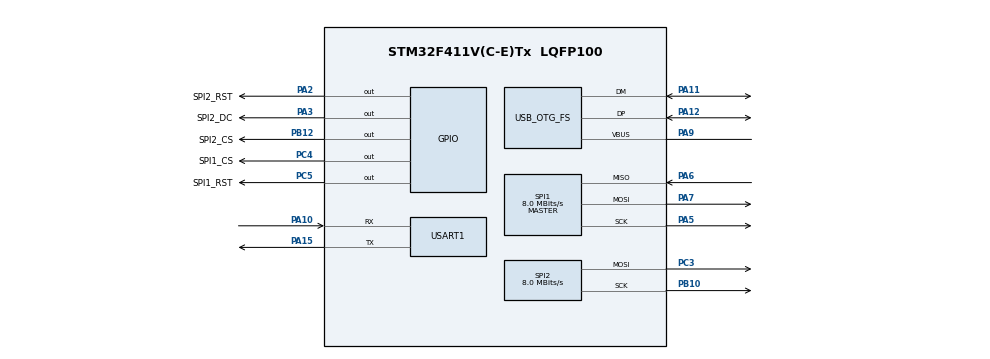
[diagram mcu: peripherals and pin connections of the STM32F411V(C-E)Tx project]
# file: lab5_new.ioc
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Mcu.Family=STM32F4
Mcu.Name=STM32F411V(C-E)Tx
Mcu.Package=LQFP100
NVIC.OTG_FS_IRQn=true\:0\:0\:false\:false\:true\:false\:true\:true
NVIC.PriorityGroup=NVIC_PRIORITYGROUP_4
NVIC.SPI2_IRQn=true\:0\:0\:false\:false\:true\:true\:true\:true
PA10.Mode=Asynchronous
PA10.Signal=USART1_RX
PA11.Mode=Device_Only
PA11.Signal=USB_OTG_FS_DM
PA12.Mode=Device_Only
PA12.Signal=USB_OTG_FS_DP
PA13.Mode=Serial_Wire
PA13.Signal=SYS_JTMS-SWDIO
PA14.Mode=Serial_Wire
PA14.Signal=SYS_JTCK-SWCLK
PA15.Mode=Asynchronous
PA15.Signal=USART1_TX
PA2.GPIO_Label=SPI2_RST
PA2.Signal=GPIO_Output
PA3.GPIO_Label=SPI2_DC
PA3.Signal=GPIO_Output
PA5.Mode=Full_Duplex_Master
PA5.Signal=SPI1_SCK
PA6.Mode=Full_Duplex_Master
PA6.Signal=SPI1_MISO
PA7.Mode=Full_Duplex_Master
PA7.Signal=SPI1_MOSI
PA9.Mode=Activate_VBUS
PA9.Signal=USB_OTG_FS_VBUS
PB10.Mode=TX_Only_Simplex_Unidirect_Master
PB10.Signal=SPI2_SCK
PB12.GPIO_Label=SPI2_CS
PB12.Signal=GPIO_Output
PC3.Mode=TX_Only_Simplex_Unidirect_Master
PC3.Signal=SPI2_MOSI
PC4.GPIO_Label=SPI1_CS
PC4.PinState=GPIO_PIN_SET
PC4.Signal=GPIO_Output
PC5.GPIO_Label=SPI1_RST
PC5.PinState=GPIO_PIN_SET
PC5.Signal=GPIO_Output
PH0\ -\ OSC_IN.Mode=HSE-External-Oscillator
PH0\ -\ OSC_IN.Signal=RCC_OSC_IN
PH1\ -\ OSC_OUT.Mode=HSE-External-Oscillator
PH1\ -\ OSC_OUT.Signal=RCC_OSC_OUT
ProjectManager.HeapSize=0x200
ProjectManager.StackSize=0x400
ProjectManager.TargetToolchain=STM32CubeIDE
RCC.48MHZClocksFreq_Value=48000000
RCC.AHBCLKDivider=RCC_SYSCLK_DIV2
RCC.AHBFreq_Value=16000000
RCC.APB1Freq_Value=16000000
RCC.APB1TimFreq_Value=16000000
RCC.APB2Freq_Value=16000000
RCC.APB2TimFreq_Value=16000000
RCC.CortexFreq_Value=16000000
RCC.HCLKFreq_Value=16000000
RCC.HSE_VALUE=25000000
RCC.HSI_VALUE=16000000
RCC.LSE_VALUE=32768
RCC.PLLM=25
RCC.PLLP=RCC_PLLP_DIV6
RCC.SYSCLKFreq_VALUE=32000000
RCC.SYSCLKSource=RCC_SYSCLKSOURCE_PLLCLK
RCC.VCOOutputFreq_Value=192000000
SPI1.CalculateBaudRate=8.0 MBits/s
SPI1.Direction=SPI_DIRECTION_2LINES
SPI1.Mode=SPI_MODE_MASTER
SPI1.VirtualType=VM_MASTER
SPI2.CalculateBaudRate=8.0 MBits/s
SPI2.Direction=SPI_DIRECTION_2LINES
SPI2.Mode=SPI_MODE_MASTER
SPI2.VirtualType=VM_MASTER
USART1.VirtualMode=VM_ASYNC
USB_DEVICE.CLASS_NAME_FS=CDC
USB_DEVICE.VirtualMode=Cdc
USB_DEVICE.VirtualModeFS=Cdc_FS
USB_OTG_FS.VirtualMode=Device_Only
VP_USB_DEVICE_VS_USB_DEVICE_CDC_FS.Mode=CDC_FS
board=custom

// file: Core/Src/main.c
/* USER CODE BEGIN Header */
/**
  ******************************************************************************
  * @file           : main.c
  * @brief          : Main program body
  ******************************************************************************
  * @attention
  *
  * Copyright (c) 2025 STMicroelectronics.
  * All rights reserved.
  *
  * This software is licensed under terms that can be found in the LICENSE file
  * in the root directory of this software component.
  * If no LICENSE file comes with this software, it is provided AS-IS.
  *
  ******************************************************************************
  */
/* USER CODE END Header */
#include "main.h"
#include "usb_device.h"

/* USER CODE BEGIN Includes */
#include <stdio.h>
#include <string.h>
#include <w5500_custom.h>
#include "dhcp.h"
#include "net.h"
#include "socket.h"
#include "ILI9341.h"
#include "llmnr.h"
/* USER CODE END Includes */

SPI_HandleTypeDef hspi1;
SPI_HandleTypeDef hspi2;

UART_HandleTypeDef huart1;

/* USER CODE BEGIN PV */
volatile uint32_t dhcp_tick_cnt = 0;
uint8_t chip_ver_g;
Screen ILI9341_Screen;

uint8_t is_websocket_active = 0;
/* USER CODE END PV */

void SystemClock_Config(void);
static void MX_GPIO_Init(void);
static void MX_SPI1_Init(void);
static void MX_USART1_UART_Init(void);
static void MX_SPI2_Init(void);

/* USER CODE BEGIN 0 */

void Timer_Callback_1s(void) {
    DHCP_time_handler();
}

/* USER CODE END 0 */

int main(void)
{

  /* MCU Configuration--------------------------------------------------------*/

  /* Reset of all peripherals, Initializes the Flash interface and the Systick. */
  HAL_Init();

  /* Configure the system clock */
  SystemClock_Config();

  /* Initialize all configured peripherals */
  MX_GPIO_Init();
  MX_SPI1_Init();
  MX_USART1_UART_Init();
  MX_SPI2_Init();
  /* USER CODE BEGIN 2 */

  ILI9341_init(&hspi2);

  Screen_Tiles_init(&ILI9341_Screen);

  ILI9341_fill_screen(&hspi2, &ILI9341_Screen, 0x0000); // 0x0000
  HAL_Delay(3000);

  printf("Resetting W5500...\r\n");

  HAL_GPIO_WritePin(GPIOC, GPIO_PIN_5, GPIO_PIN_RESET);
  HAL_Delay(10);
  HAL_GPIO_WritePin(GPIOC, GPIO_PIN_5, GPIO_PIN_SET);
  HAL_Delay(100);

  W5500_Init();
  Net_Init();

  status_init();

    // Initialize USB CDC device
  MX_USB_DEVICE_Init();

  // --- Start HTTP Server on Socket 1 ---
  uint8_t sock = 1;

    if(socket(sock, Sn_MR_TCP, 80, 0) == sock) {
        listen(sock);
        printf("Server started on port 80\r\n");
    } else {
        printf("Failed to open socket\r\n");
    }

    // --- Start LLMNR on Socket 2 ---
      uint8_t sock_llmnr = 2; // <--- 2. Виділяємо окремий сокет для LLMNR (UDP)
      LLMNR_Init(sock_llmnr); // <--- 3. Ініціалізуємо LLMNR
  /* USER CODE END 2 */
      uint32_t last_status_ms = HAL_GetTick();
  /* Infinite loop */
  while (1)
  {

    /* USER CODE BEGIN 3 */
	  uint32_t now = HAL_GetTick();

	  if ((now - last_status_ms) >= 1000)
		{
			last_status_ms = now;
			status_update();
		}

	  wiz_NetInfo cur_net_info;

	  wizchip_getnetinfo(&cur_net_info);

	  if (cur_net_info.dhcp == NETINFO_DHCP) {
	       static uint32_t sec_timer = 0;
	       if (HAL_GetTick() - sec_timer >= 1000) {
	          sec_timer = HAL_GetTick();
	          DHCP_time_handler();
	       }
	       DHCP_run();
	  }

	  // ========== HTTP SERVER LOOP ==========
	  uint8_t status = getSn_SR(sock);

	  static uint8_t buffer[1024];

	  if (status == SOCK_CLOSED) {
		  if(socket(sock, Sn_MR_TCP, 80, 0) == sock) {
			  listen(sock);
			  is_websocket_active = 0; // Reset flag
			  printf("Socket Re-opened\r\n");
		  }
	  }

	  if (status == SOCK_ESTABLISHED) {
		if (getSn_RX_RSR(sock) > 0) {
		  int32_t recv_len = recv(sock, buffer, sizeof(buffer));

		  if (recv_len > 0) {
			  if (!is_websocket_active && strstr((char*)buffer, "Upgrade: websocket")) {
					  printf("WebSocket Upgrade Request Received\r\n");
					  if (WS_PerformHandshake(sock, (char*)buffer)) { //
						  is_websocket_active = 1;
						  printf("WebSocket Handshake Success!\r\n");
						  // IMPORTANT: DO NOT DISCONNECT HERE
				  }
			  }

			  // --- GET /status ---
			  else if (strstr((char*)buffer, "GET /status") != NULL) {

				  char json[256];
				  build_status_json(json, sizeof(json));

				  char header[128];
				  sprintf(header,
					  "HTTP/1.1 200 OK\r\n"
					  "Content-Type: application/json\r\n"
					  "Content-Length: %d\r\n\r\n",
					  (int)strlen(json)
				  );

				  send(sock, (uint8_t *)header, strlen(header));
				  send(sock, (uint8_t *)json, strlen(json));
			  }

			  // --- GET / ---
			  else if (!is_websocket_active && strstr((char*)buffer, "GET / ")) {
			                  // Updated HTML to use WebSocket Client (ws://)
			                  const char *html =
			                      "<html><head><title>STM32 WS</title></head><body>"
			                      "<h1>STM32 Monitor</h1>"
			                      "<div id='d' style='font-size:20px;font-family:monospace;'>Waiting...</div>"
			                      "<script>"
			                      "var ws = new WebSocket('ws://' + location.host);"
			                      "ws.onmessage = function(e){ document.getElementById('d').innerText = e.data; };"
			                      "ws.onclose = function(){ document.getElementById('d').innerText += ' (Closed)'; };"
			                      "</script>"
			                      "</body></html>";

			                  char header[128];
			                  sprintf(header,
			                      "HTTP/1.1 200 OK\r\n"
			                      "Content-Type: text/html\r\n"
			                      "Content-Length: %d\r\n\r\n",
			                      strlen(html)
			                  );
			                  send(sock, (uint8_t *)header, strlen(header));
			                  send(sock, (uint8_t *)html, strlen(html));

			                  // For standard HTTP, we MUST disconnect to finish the load
			                  disconnect(sock);
			  }

		  }

		}
	  }

	  if (status == SOCK_CLOSE_WAIT) {
	          disconnect(sock);
	          is_websocket_active = 0;
	          printf("Client Disconnected\r\n");
	  }
	  if (is_websocket_active) {
	              static uint32_t ws_timer = 0;
	              if (HAL_GetTick() - ws_timer >= 500) { // Send every 500ms
	                  ws_timer += 500;

	                  char json[128];
	                  // Simulate changing data
	                  sprintf(json, "{\"tick\":%lu, \"adc\":%d}", HAL_GetTick(), rand()%4096);

	                  WS_SendText(sock, json); //
	              }
	  }
	  // --- LLMNR Process ---
	  LLMNR_Process(sock_llmnr);
  }

  /* USER CODE END 3 */
}

void SystemClock_Config(void)
{
  RCC_OscInitTypeDef RCC_OscInitStruct = {0};
  RCC_ClkInitTypeDef RCC_ClkInitStruct = {0};

  /* Увімкнути живлення і виставити шкалу напруги */
  __HAL_RCC_PWR_CLK_ENABLE();
  __HAL_PWR_VOLTAGESCALING_CONFIG(PWR_REGULATOR_VOLTAGE_SCALE2);

  /* Налаштовуємо осцилятори: HSE + PLL */
  RCC_OscInitStruct.OscillatorType = RCC_OSCILLATORTYPE_HSE;
  RCC_OscInitStruct.HSEState = RCC_HSE_ON;
  RCC_OscInitStruct.PLL.PLLState = RCC_PLL_ON;
  RCC_OscInitStruct.PLL.PLLSource = RCC_PLLSOURCE_HSE;

  /* HSE=8MHz:
   * PLLM = 8   → VCO_IN = 1 MHz
   * PLLN = 336 → VCO_OUT = 336 MHz
   * PLLP = 4   → SYSCLK = 84 MHz
   * PLLQ = 7   → 336/7 = 48 MHz для USB
   */
  RCC_OscInitStruct.PLL.PLLM = 8;
  RCC_OscInitStruct.PLL.PLLN = 336;
  RCC_OscInitStruct.PLL.PLLP = RCC_PLLP_DIV4;
  RCC_OscInitStruct.PLL.PLLQ = 7;

  if (HAL_RCC_OscConfig(&RCC_OscInitStruct) != HAL_OK)
  {
    Error_Handler();
  }

  /* Шини */
  RCC_ClkInitStruct.ClockType = RCC_CLOCKTYPE_HCLK |
                                RCC_CLOCKTYPE_SYSCLK |
                                RCC_CLOCKTYPE_PCLK1 |
                                RCC_CLOCKTYPE_PCLK2;

  RCC_ClkInitStruct.SYSCLKSource = RCC_SYSCLKSOURCE_PLLCLK;  // 84 MHz
  RCC_ClkInitStruct.AHBCLKDivider = RCC_SYSCLK_DIV1;         // HCLK = 84 MHz
  RCC_ClkInitStruct.APB1CLKDivider = RCC_HCLK_DIV2;          // PCLK1 = 42 MHz
  RCC_ClkInitStruct.APB2CLKDivider = RCC_HCLK_DIV1;          // PCLK2 = 84 MHz

  if (HAL_RCC_ClockConfig(&RCC_ClkInitStruct, FLASH_LATENCY_2) != HAL_OK)
  {
    Error_Handler();
  }
}

static void MX_SPI1_Init(void)
{

  /* SPI1 parameter configuration*/
  hspi1.Instance = SPI1;
  hspi1.Init.Mode = SPI_MODE_MASTER;
  hspi1.Init.Direction = SPI_DIRECTION_2LINES;
  hspi1.Init.DataSize = SPI_DATASIZE_8BIT;
  hspi1.Init.CLKPolarity = SPI_POLARITY_LOW;
  hspi1.Init.CLKPhase = SPI_PHASE_1EDGE;
  hspi1.Init.NSS = SPI_NSS_SOFT;
  hspi1.Init.BaudRatePrescaler = SPI_BAUDRATEPRESCALER_2;
  hspi1.Init.FirstBit = SPI_FIRSTBIT_MSB;
  hspi1.Init.TIMode = SPI_TIMODE_DISABLE;
  hspi1.Init.CRCCalculation = SPI_CRCCALCULATION_DISABLE;
  hspi1.Init.CRCPolynomial = 10;
  if (HAL_SPI_Init(&hspi1) != HAL_OK)
  {
    Error_Handler();
  }

}

static void MX_SPI2_Init(void)
{

  /* SPI2 parameter configuration*/
  hspi2.Instance = SPI2;
  hspi2.Init.Mode = SPI_MODE_MASTER;
  hspi2.Init.Direction = SPI_DIRECTION_2LINES;
  hspi2.Init.DataSize = SPI_DATASIZE_8BIT;
  hspi2.Init.CLKPolarity = SPI_POLARITY_LOW;
  hspi2.Init.CLKPhase = SPI_PHASE_1EDGE;
  hspi2.Init.NSS = SPI_NSS_SOFT;
  hspi2.Init.BaudRatePrescaler = SPI_BAUDRATEPRESCALER_2;
  hspi2.Init.FirstBit = SPI_FIRSTBIT_MSB;
  hspi2.Init.TIMode = SPI_TIMODE_DISABLE;
  hspi2.Init.CRCCalculation = SPI_CRCCALCULATION_DISABLE;
  hspi2.Init.CRCPolynomial = 10;
  if (HAL_SPI_Init(&hspi2) != HAL_OK)
  {
    Error_Handler();
  }

}

static void MX_USART1_UART_Init(void)
{

  huart1.Instance = USART1;
  huart1.Init.BaudRate = 115200;
  huart1.Init.WordLength = UART_WORDLENGTH_8B;
  huart1.Init.StopBits = UART_STOPBITS_1;
  huart1.Init.Parity = UART_PARITY_NONE;
  huart1.Init.Mode = UART_MODE_TX_RX;
  huart1.Init.HwFlowCtl = UART_HWCONTROL_NONE;
  huart1.Init.OverSampling = UART_OVERSAMPLING_16;
  if (HAL_UART_Init(&huart1) != HAL_OK)
  {
    Error_Handler();
  }

}

static void MX_GPIO_Init(void)
{
  GPIO_InitTypeDef GPIO_InitStruct = {0};

  /* GPIO Ports Clock Enable */
  __HAL_RCC_GPIOH_CLK_ENABLE();
  __HAL_RCC_GPIOC_CLK_ENABLE();
  __HAL_RCC_GPIOA_CLK_ENABLE();
  __HAL_RCC_GPIOB_CLK_ENABLE();

  /*Configure GPIO pin Output Level */
  HAL_GPIO_WritePin(GPIOA, SPI2_RST_Pin|SPI2_DC_Pin, GPIO_PIN_RESET);

  /*Configure GPIO pin Output Level */
  HAL_GPIO_WritePin(GPIOC, SPI1_CS_Pin|SPI1_RST_Pin, GPIO_PIN_SET);

  /*Configure GPIO pin Output Level */
  HAL_GPIO_WritePin(SPI2_CS_GPIO_Port, SPI2_CS_Pin, GPIO_PIN_RESET);

  /*Configure GPIO pins : SPI2_RST_Pin SPI2_DC_Pin */
  GPIO_InitStruct.Pin = SPI2_RST_Pin|SPI2_DC_Pin;
  GPIO_InitStruct.Mode = GPIO_MODE_OUTPUT_PP;
  GPIO_InitStruct.Pull = GPIO_NOPULL;
  GPIO_InitStruct.Speed = GPIO_SPEED_FREQ_LOW;
  HAL_GPIO_Init(GPIOA, &GPIO_InitStruct);

  /*Configure GPIO pins : SPI1_CS_Pin SPI1_RST_Pin */
  GPIO_InitStruct.Pin = SPI1_CS_Pin|SPI1_RST_Pin;
  GPIO_InitStruct.Mode = GPIO_MODE_OUTPUT_PP;
  GPIO_InitStruct.Pull = GPIO_NOPULL;
  GPIO_InitStruct.Speed = GPIO_SPEED_FREQ_LOW;
  HAL_GPIO_Init(GPIOC, &GPIO_InitStruct);

  /*Configure GPIO pin : SPI2_CS_Pin */
  GPIO_InitStruct.Pin = SPI2_CS_Pin;
  GPIO_InitStruct.Mode = GPIO_MODE_OUTPUT_PP;
  GPIO_InitStruct.Pull = GPIO_NOPULL;
  GPIO_InitStruct.Speed = GPIO_SPEED_FREQ_LOW;
  HAL_GPIO_Init(SPI2_CS_GPIO_Port, &GPIO_InitStruct);

}

void Error_Handler(void)
{
  __disable_irq();
  while (1)
  {
  }
}
